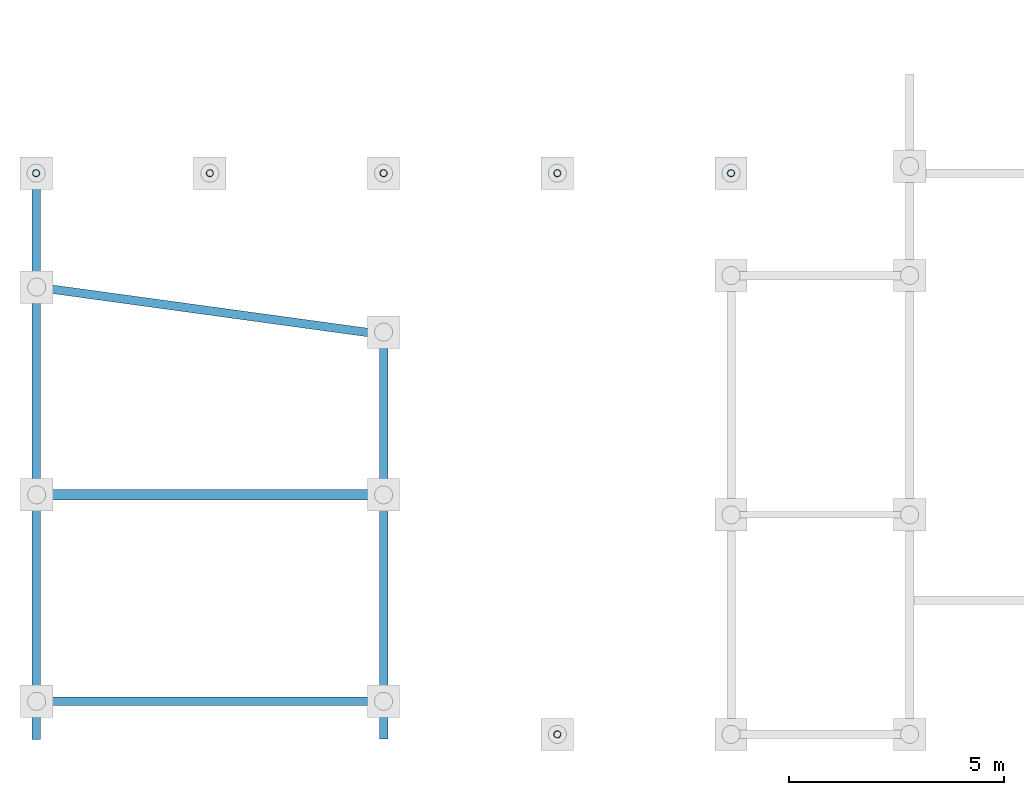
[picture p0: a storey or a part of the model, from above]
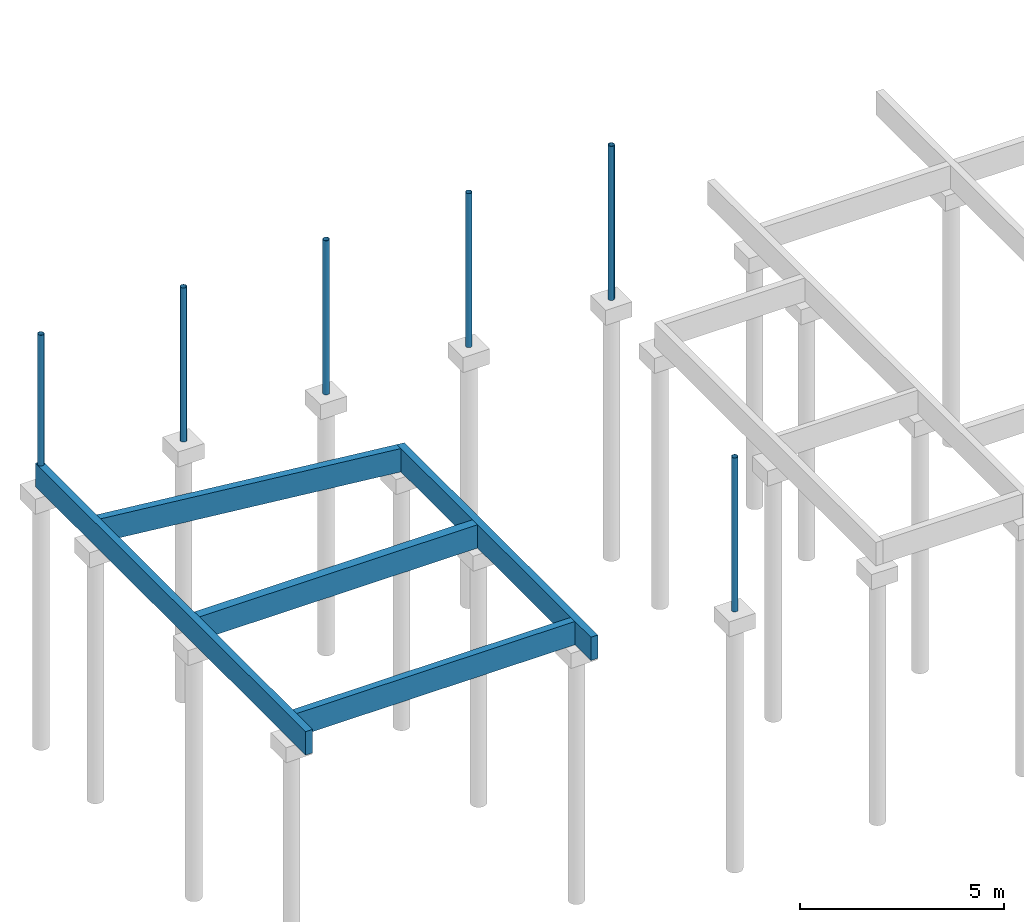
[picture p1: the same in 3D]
Properties of the parts of a building model (IFC2X3)

# File
Description: ViewDefinition [CoordinationView_V2.0]
File name: 0001
Time: 2016-10-13T17:21:40
Written by: The EXPRESS Data Manager Version 5.02.0100.07 : 28 Aug 2013
Made in: 20160225_1515(x64) - Exporter 17.0.416.0 - Alternate UI 17.12.14.0
Comment: STEP Physical File produced by: The EXPRESS Data Manager Version 5.02.0100.07 : 28 Aug 2013 * Module: EDMstepFileFactory/EDMstandAlone * Creation date: Thu Oct 13 17:21:40 2016 * Host: PC-FOURIER-1 * Database: D:\TMP\{57117633-1248-46CD-8CDE-73961FE649AC}\ifc * Database version: 5507 * Database creation date: Thu Oct 13 17:21:37 2016 * Schema: IFC2X3 * Model: DataRepository.ifc * Model creation date: Thu Oct 13 17:21:37 2016 * Header model: DataRepository.ifc_HeaderModel * Header model creation date: Thu Oct 13 17:21:37 2016 * EDMuser: sdai-user * EDMgroup: sdai-group * License ID and type: 5605 : Permanent license. Expiry date: * EDMstepFileFactory options: 020000

# IfcProject, 0001
LongName: Nom du projet; Phase: Etat du projet

# IfcSite, Default
RefLatitude: 48, 52, 0, 117187; RefLongitude: 2, 19, 59, 880409; RefElevation: 0 m

# IfcBuilding
Pset_BuildingCommon - NumberOfStoreys: 2

# IfcBuildingStorey (2)
Name | LongName | Elevation (m)
Fondation | Fondation | -0.77
Niveau 0 | Niveau 0 | -1.94916e-14

# IfcBeam: Longrine 0.20 x 0.7, Poutre rectangulaire - Béton:Longrine 0.20 x 0.7:253660
In: Fondation
Material: Béton - Béton coulé sur place
Pset_BeamCommon - LoadBearing: yes; IsExternal: no; Slope: 0 deg; Reference: Longrine 0.20 x 0.7; Span: 23.15 m

# IfcBeam: Poutre rectangulaire - Béton:Longrine 0.15 x 0.70:254038, Poutre rectangulaire - Béton:Longrine 0.15 x 0.70:254083
In: Fondation
Material: Béton - Béton coulé sur place
Pset_BeamCommon - LoadBearing: yes; IsExternal: no; Slope: 0 deg; Reference: Longrine 0.15 x 0.70; Span: 4.153 m

# IfcBeam: Poutre rectangulaire - Béton:Longrine 0.20 x 0.7:252653 (13)
In: Fondation
Material: Béton - Béton coulé sur place
Pset_BeamCommon - LoadBearing: yes; IsExternal: no; Slope: 0 deg; Reference: Longrine 0.20 x 0.7
Name (Poutre rectangulaire - Béton:Longrine 0.20 x 0.7:...) | Span (m)
252734 | 13.24
253108 | 9.395
253137 | 8.08
253244 | 4.053
253293 | 10.67
253375 | 15.35
253405 | 4.153
253493 | 5.5
253616 | 16.7
253689 | 13.16
253718 | 17.65
253861 | 17.65
253937 | 8.155

# IfcBeam: Poutre rectangulaire - Béton:Longrine 0.25 x 0.70:253967, Poutre rectangulaire - Béton:Longrine 0.25 x 0.70:254013
In: Fondation
Material: Béton - Béton coulé sur place
Pset_BeamCommon - LoadBearing: yes; IsExternal: no; Slope: 0 deg; Reference: Longrine 0.25 x 0.70; Span: 8.08 m

# IfcColumn: RO168.3x8 (6)
In: Fondation
Type - ElementType: RO168.3x8; PredefinedType: COLUMN; Material: Acier structurel - S235
Pset_ColumnCommon - LoadBearing: yes; Reference: RO168.3x8; IsExternal: no; Slope: 0 deg
Name (Poteau RO (EN 10219-2):RO168.3x8:...)
250386
250422
250537
250618
250681
256828

# IfcSlab: Base rectangulaire:Semelle 0.75 x 0.75 x 0.45 (31)
In: Fondation
PredefinedType: FLOOR; Material: Béton - Béton coulé sur place
Pset_SlabCommon - LoadBearing: yes; IsExternal: no; PitchAngle: 0 deg; Reference: Semelle 0.75 x 0.75 x 0.45
Name (Base rectangulaire:Semelle 0.75 x 0.75 x 0.45:...)
254622
256209
256303
256363
256376
256389
256402
256415
256426
256437
256495
256506
256578
256595
256608
256623
256634
256645
256656
256667
256686
256699
256710
256721
256734
256747
256760
256773
256784
256795
256806

# IfcSlab: Pieu-Conduite en acier:Pieu 420mm (31)
In: Fondation
PredefinedType: FLOOR; Classification: A1020130 Piles - Steel Pipe (Uniformat); Material: Maçonnerie - Béton coulé sur place
Pset_SlabCommon - LoadBearing: yes; IsExternal: no; PitchAngle: 0 deg; Reference: Pieu 420mm
Name (Pieu-Conduite en acier:Pieu 420mm:...)
256006
256211
256305
256365
256378
256391
256404
256417
256428
256439
256497
256508
256580
256597
256610
256625
256636
256647
256658
256669
256688
256701
256712
256723
256736
256749
256762
256775
256786
256797
256808

# IfcSlab: Sol:Dalle en béton - 210 mm (4)
In: Niveau 0
PredefinedType: FLOOR; Material: Maçonnerie - Béton 0.21 m
Pset_SlabCommon - LoadBearing: yes; IsExternal: no; Reference: Dalle en béton - 210 mm; PitchAngle: 0 deg
Name (Sol:Dalle en béton - 210 mm:...)
251143
251659
251710
251742

# IfcWall: Mur de base:Générique - Ext. 200 mm (2)
In: Niveau 0
Material: Mur par défaut
Pset_WallCommon - Reference: Générique - Ext. 200 mm; LoadBearing: yes; ExtendToStructure: no; IsExternal: yes
Name (Mur de base:Générique - Ext. 200 mm:...)
243940
244052

# IfcWallStandardCase: Mur de base:Générique - Ext. 150 mm, Mur de base:Générique - Ext. 150 mm:245482
In: Niveau 0
Type - PredefinedType: STANDARD; Material: Mur par défaut 0.15 m
Pset_WallCommon - LoadBearing: yes; ExtendToStructure: no; IsExternal: yes; Reference: Générique - Ext. 150 mm

# IfcWallStandardCase: Mur de base:Générique - Ext. 200 mm (18)
In: Niveau 0
Material: Mur par défaut 0.2 m
Pset_WallCommon - Reference: Générique - Ext. 200 mm; ExtendToStructure: no; IsExternal: yes
Name (Mur de base:Générique - Ext. 200 mm:...) | LoadBearing
244156 | yes
244324 | yes
244429 | yes
244660 | yes
244792 | yes
244896 | yes
245001 | yes
245579 | no
245706 | yes
245844 | yes
245973 | yes
245991 | no
246083 | yes
246252 | yes
246309 | no
248107 | yes
248249 | yes
248828 | no
